VERSION 5.8 ;
DIVIDERCHAR "/" ;
BUSBITCHARS "[]" ;
UNITS
  DATABASE MICRONS 1000 ;
END UNITS
MANUFACTURINGGRID 0.001 ;
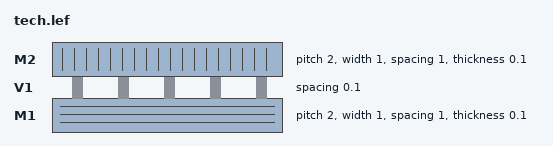
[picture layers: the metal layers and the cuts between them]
LAYER M1
  TYPE ROUTING ;
  DIRECTION HORIZONTAL ;
  PITCH 2 ;
  WIDTH 1 ;
  SPACING 1 ;
  THICKNESS 0.1 ;
  ANTENNAAREARATIO 2 ;
  ANTENNACUMAREARATIO 3 ;
  ANTENNASIDEAREARATIO 1 ;
  ANTENNACUMSIDEAREARATIO 1.5 ;
END M1
LAYER V1
  TYPE CUT ;
  SPACING 0.1 ;
  ANTENNAAREARATIO 0.01 ;
  ANTENNACUMAREARATIO 0.02 ;
END V1
LAYER M2
  TYPE ROUTING ;
  DIRECTION VERTICAL ;
  PITCH 2 ;
  WIDTH 1 ;
  SPACING 1 ;
  THICKNESS 0.1 ;
  ANTENNAAREARATIO 2 ;
  ANTENNACUMAREARATIO 7 ;
  ANTENNASIDEAREARATIO 0.5 ;
  ANTENNACUMSIDEAREARATIO 1.5 ;
END M2
VIA V12 DEFAULT
  LAYER M1 ;
    RECT -0.5 -0.5 0.5 0.5 ;
  LAYER V1 ;
    RECT -0.1 -0.1 0.1 0.1 ;
  LAYER M2 ;
    RECT -0.5 -0.5 0.5 0.5 ;
END V12
SITE CORE
  CLASS CORE ;
  SIZE 1 BY 1 ;
  SYMMETRY X Y ;
END CORE
END LIBRARY
